VERSION 5.7 ;
  NOWIREEXTENSIONATPIN ON ;
  DIVIDERCHAR "/" ;
  BUSBITCHARS "[]" ;
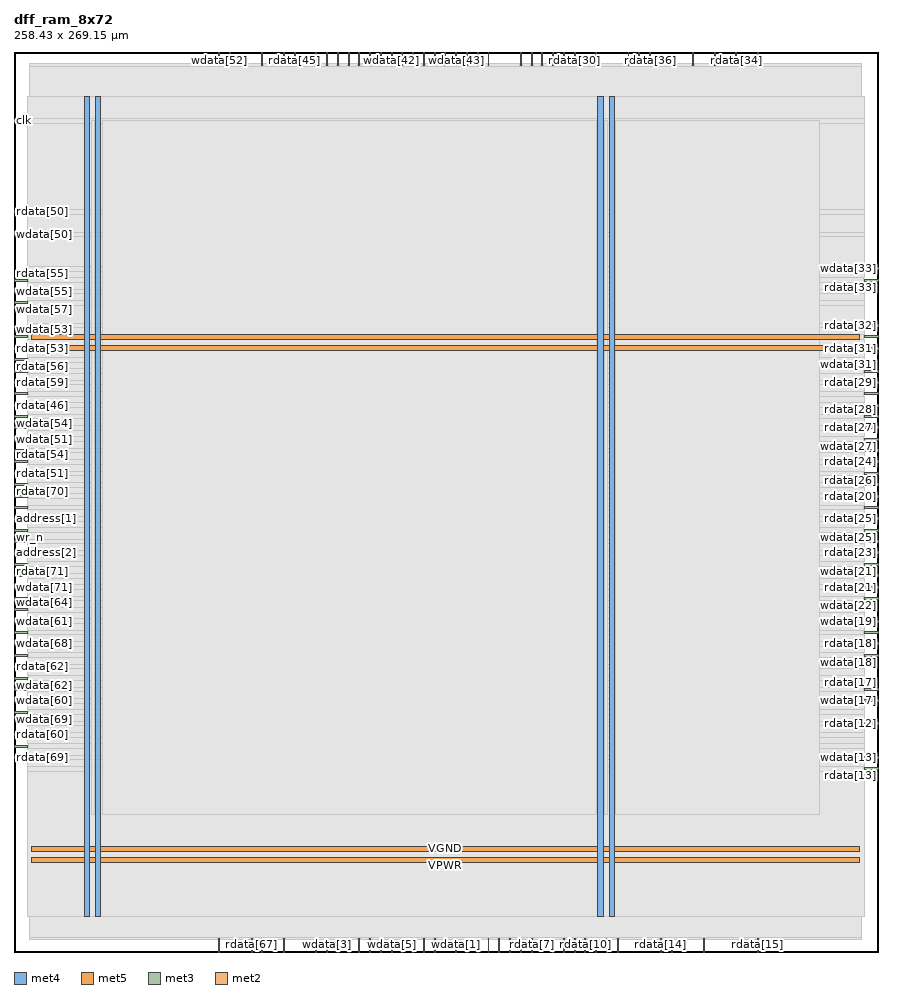
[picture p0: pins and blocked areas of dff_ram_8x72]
MACRO dff_ram_8x72
  CLASS BLOCK ;
  FOREIGN dff_ram_8x72 ;
  ORIGIN 0.000 0.000 ;
  SIZE 258.430 BY 269.150 ;
  PIN VGND
    DIRECTION INOUT ;
    USE GROUND ;
    PORT
      LAYER met4 ;
        RECT 24.340 10.640 25.940 255.920 ;
    END
    PORT
      LAYER met4 ;
        RECT 177.940 10.640 179.540 255.920 ;
    END
    PORT
      LAYER met5 ;
        RECT 5.280 30.030 252.780 31.630 ;
    END
    PORT
      LAYER met5 ;
        RECT 5.280 183.210 252.780 184.810 ;
    END
  END VGND
  PIN VPWR
    DIRECTION INOUT ;
    USE POWER ;
    PORT
      LAYER met4 ;
        RECT 21.040 10.640 22.640 255.920 ;
    END
    PORT
      LAYER met4 ;
        RECT 174.640 10.640 176.240 255.920 ;
    END
    PORT
      LAYER met5 ;
        RECT 5.280 26.730 252.780 28.330 ;
    END
    PORT
      LAYER met5 ;
        RECT 5.280 179.910 252.780 181.510 ;
    END
  END VPWR
  PIN address[0]
    DIRECTION INPUT ;
    USE SIGNAL ;
    ANTENNAGATEAREA 0.213000 ;
    PORT
      LAYER met3 ;
        RECT 0.000 132.640 4.000 133.240 ;
    END
  END address[0]
  PIN address[1]
    DIRECTION INPUT ;
    USE SIGNAL ;
    ANTENNAGATEAREA 0.213000 ;
    PORT
      LAYER met3 ;
        RECT 0.000 129.240 4.000 129.840 ;
    END
  END address[1]
  PIN address[2]
    DIRECTION INPUT ;
    USE SIGNAL ;
    ANTENNAGATEAREA 0.126000 ;
    PORT
      LAYER met3 ;
        RECT 0.000 119.040 4.000 119.640 ;
    END
  END address[2]
  PIN clk
    DIRECTION INPUT ;
    USE SIGNAL ;
    ANTENNAGATEAREA 0.852000 ;
    PORT
      LAYER met3 ;
        RECT 0.000 248.240 4.000 248.840 ;
    END
  END clk
  PIN rdata[0]
    DIRECTION OUTPUT TRISTATE ;
    USE SIGNAL ;
    ANTENNADIFFAREA 0.795200 ;
    PORT
      LAYER met2 ;
        RECT 119.230 0.000 119.510 4.000 ;
    END
  END rdata[0]
  PIN rdata[10]
    DIRECTION OUTPUT TRISTATE ;
    USE SIGNAL ;
    ANTENNADIFFAREA 0.795200 ;
    PORT
      LAYER met2 ;
        RECT 170.750 0.000 171.030 4.000 ;
    END
  END rdata[10]
  PIN rdata[11]
    DIRECTION OUTPUT TRISTATE ;
    USE SIGNAL ;
    ANTENNADIFFAREA 0.795200 ;
    PORT
      LAYER met2 ;
        RECT 173.970 0.000 174.250 4.000 ;
    END
  END rdata[11]
  PIN rdata[12]
    DIRECTION OUTPUT TRISTATE ;
    USE SIGNAL ;
    ANTENNADIFFAREA 0.795200 ;
    PORT
      LAYER met3 ;
        RECT 254.430 68.040 258.430 68.640 ;
    END
  END rdata[12]
  PIN rdata[13]
    DIRECTION OUTPUT TRISTATE ;
    USE SIGNAL ;
    ANTENNADIFFAREA 0.795200 ;
    PORT
      LAYER met3 ;
        RECT 254.430 54.440 258.430 55.040 ;
    END
  END rdata[13]
  PIN rdata[14]
    DIRECTION OUTPUT TRISTATE ;
    USE SIGNAL ;
    ANTENNADIFFAREA 0.795200 ;
    PORT
      LAYER met2 ;
        RECT 193.290 0.000 193.570 4.000 ;
    END
  END rdata[14]
  PIN rdata[15]
    DIRECTION OUTPUT TRISTATE ;
    USE SIGNAL ;
    ANTENNADIFFAREA 0.795200 ;
    PORT
      LAYER met2 ;
        RECT 222.270 0.000 222.550 4.000 ;
    END
  END rdata[15]
  PIN rdata[16]
    DIRECTION OUTPUT TRISTATE ;
    USE SIGNAL ;
    ANTENNADIFFAREA 0.795200 ;
    PORT
      LAYER met2 ;
        RECT 196.510 0.000 196.790 4.000 ;
    END
  END rdata[16]
  PIN rdata[17]
    DIRECTION OUTPUT TRISTATE ;
    USE SIGNAL ;
    ANTENNADIFFAREA 0.445500 ;
    PORT
      LAYER met3 ;
        RECT 254.430 78.240 258.430 78.840 ;
    END
  END rdata[17]
  PIN rdata[18]
    DIRECTION OUTPUT TRISTATE ;
    USE SIGNAL ;
    ANTENNADIFFAREA 0.795200 ;
    PORT
      LAYER met3 ;
        RECT 254.430 91.840 258.430 92.440 ;
    END
  END rdata[18]
  PIN rdata[19]
    DIRECTION OUTPUT TRISTATE ;
    USE SIGNAL ;
    ANTENNADIFFAREA 0.795200 ;
    PORT
      LAYER met3 ;
        RECT 254.430 95.240 258.430 95.840 ;
    END
  END rdata[19]
  PIN rdata[1]
    DIRECTION OUTPUT TRISTATE ;
    USE SIGNAL ;
    ANTENNADIFFAREA 0.795200 ;
    PORT
      LAYER met2 ;
        RECT 144.990 0.000 145.270 4.000 ;
    END
  END rdata[1]
  PIN rdata[20]
    DIRECTION OUTPUT TRISTATE ;
    USE SIGNAL ;
    ANTENNADIFFAREA 0.795200 ;
    PORT
      LAYER met3 ;
        RECT 254.430 136.040 258.430 136.640 ;
    END
  END rdata[20]
  PIN rdata[21]
    DIRECTION OUTPUT TRISTATE ;
    USE SIGNAL ;
    ANTENNADIFFAREA 0.795200 ;
    PORT
      LAYER met3 ;
        RECT 254.430 108.840 258.430 109.440 ;
    END
  END rdata[21]
  PIN rdata[22]
    DIRECTION OUTPUT TRISTATE ;
    USE SIGNAL ;
    ANTENNADIFFAREA 0.795200 ;
    PORT
      LAYER met3 ;
        RECT 254.430 112.240 258.430 112.840 ;
    END
  END rdata[22]
  PIN rdata[23]
    DIRECTION OUTPUT TRISTATE ;
    USE SIGNAL ;
    ANTENNADIFFAREA 0.795200 ;
    PORT
      LAYER met3 ;
        RECT 254.430 119.040 258.430 119.640 ;
    END
  END rdata[23]
  PIN rdata[24]
    DIRECTION OUTPUT TRISTATE ;
    USE SIGNAL ;
    ANTENNADIFFAREA 0.795200 ;
    PORT
      LAYER met3 ;
        RECT 254.430 146.240 258.430 146.840 ;
    END
  END rdata[24]
  PIN rdata[25]
    DIRECTION OUTPUT TRISTATE ;
    USE SIGNAL ;
    ANTENNADIFFAREA 0.795200 ;
    PORT
      LAYER met3 ;
        RECT 254.430 129.240 258.430 129.840 ;
    END
  END rdata[25]
  PIN rdata[26]
    DIRECTION OUTPUT TRISTATE ;
    USE SIGNAL ;
    ANTENNADIFFAREA 0.795200 ;
    PORT
      LAYER met3 ;
        RECT 254.430 142.840 258.430 143.440 ;
    END
  END rdata[26]
  PIN rdata[27]
    DIRECTION OUTPUT TRISTATE ;
    USE SIGNAL ;
    ANTENNADIFFAREA 0.795200 ;
    PORT
      LAYER met3 ;
        RECT 254.430 156.440 258.430 157.040 ;
    END
  END rdata[27]
  PIN rdata[28]
    DIRECTION OUTPUT TRISTATE ;
    USE SIGNAL ;
    ANTENNADIFFAREA 0.795200 ;
    PORT
      LAYER met3 ;
        RECT 254.430 159.840 258.430 160.440 ;
    END
  END rdata[28]
  PIN rdata[29]
    DIRECTION OUTPUT TRISTATE ;
    USE SIGNAL ;
    ANTENNADIFFAREA 0.795200 ;
    PORT
      LAYER met3 ;
        RECT 254.430 170.040 258.430 170.640 ;
    END
  END rdata[29]
  PIN rdata[2]
    DIRECTION OUTPUT TRISTATE ;
    USE SIGNAL ;
    ANTENNADIFFAREA 0.795200 ;
    PORT
      LAYER met2 ;
        RECT 125.670 0.000 125.950 4.000 ;
    END
  END rdata[2]
  PIN rdata[30]
    DIRECTION OUTPUT TRISTATE ;
    USE SIGNAL ;
    ANTENNADIFFAREA 0.795200 ;
    PORT
      LAYER met2 ;
        RECT 167.530 265.150 167.810 269.150 ;
    END
  END rdata[30]
  PIN rdata[31]
    DIRECTION OUTPUT TRISTATE ;
    USE SIGNAL ;
    ANTENNADIFFAREA 0.445500 ;
    PORT
      LAYER met3 ;
        RECT 254.430 180.240 258.430 180.840 ;
    END
  END rdata[31]
  PIN rdata[32]
    DIRECTION OUTPUT TRISTATE ;
    USE SIGNAL ;
    ANTENNADIFFAREA 0.445500 ;
    PORT
      LAYER met3 ;
        RECT 254.430 187.040 258.430 187.640 ;
    END
  END rdata[32]
  PIN rdata[33]
    DIRECTION OUTPUT TRISTATE ;
    USE SIGNAL ;
    ANTENNADIFFAREA 0.445500 ;
    PORT
      LAYER met3 ;
        RECT 254.430 200.640 258.430 201.240 ;
    END
  END rdata[33]
  PIN rdata[34]
    DIRECTION OUTPUT TRISTATE ;
    USE SIGNAL ;
    ANTENNADIFFAREA 0.795200 ;
    PORT
      LAYER met2 ;
        RECT 215.830 265.150 216.110 269.150 ;
    END
  END rdata[34]
  PIN rdata[35]
    DIRECTION OUTPUT TRISTATE ;
    USE SIGNAL ;
    ANTENNADIFFAREA 0.795200 ;
    PORT
      LAYER met2 ;
        RECT 183.630 265.150 183.910 269.150 ;
    END
  END rdata[35]
  PIN rdata[36]
    DIRECTION OUTPUT TRISTATE ;
    USE SIGNAL ;
    ANTENNADIFFAREA 0.795200 ;
    PORT
      LAYER met2 ;
        RECT 190.070 265.150 190.350 269.150 ;
    END
  END rdata[36]
  PIN rdata[37]
    DIRECTION OUTPUT TRISTATE ;
    USE SIGNAL ;
    ANTENNADIFFAREA 0.795200 ;
    PORT
      LAYER met2 ;
        RECT 164.310 265.150 164.590 269.150 ;
    END
  END rdata[37]
  PIN rdata[38]
    DIRECTION OUTPUT TRISTATE ;
    USE SIGNAL ;
    ANTENNADIFFAREA 0.795200 ;
    PORT
      LAYER met2 ;
        RECT 209.390 265.150 209.670 269.150 ;
    END
  END rdata[38]
  PIN rdata[39]
    DIRECTION OUTPUT TRISTATE ;
    USE SIGNAL ;
    ANTENNADIFFAREA 0.795200 ;
    PORT
      LAYER met2 ;
        RECT 161.090 265.150 161.370 269.150 ;
    END
  END rdata[39]
  PIN rdata[3]
    DIRECTION OUTPUT TRISTATE ;
    USE SIGNAL ;
    ANTENNADIFFAREA 0.795200 ;
    PORT
      LAYER met2 ;
        RECT 103.130 0.000 103.410 4.000 ;
    END
  END rdata[3]
  PIN rdata[40]
    DIRECTION OUTPUT TRISTATE ;
    USE SIGNAL ;
    ANTENNADIFFAREA 0.795200 ;
    PORT
      LAYER met2 ;
        RECT 138.550 265.150 138.830 269.150 ;
    END
  END rdata[40]
  PIN rdata[41]
    DIRECTION OUTPUT TRISTATE ;
    USE SIGNAL ;
    ANTENNADIFFAREA 0.795200 ;
    PORT
      LAYER met2 ;
        RECT 106.350 265.150 106.630 269.150 ;
    END
  END rdata[41]
  PIN rdata[42]
    DIRECTION OUTPUT TRISTATE ;
    USE SIGNAL ;
    ANTENNADIFFAREA 0.795200 ;
    PORT
      LAYER met2 ;
        RECT 119.230 265.150 119.510 269.150 ;
    END
  END rdata[42]
  PIN rdata[43]
    DIRECTION OUTPUT TRISTATE ;
    USE SIGNAL ;
    ANTENNADIFFAREA 0.795200 ;
    PORT
      LAYER met2 ;
        RECT 141.770 265.150 142.050 269.150 ;
    END
  END rdata[43]
  PIN rdata[44]
    DIRECTION OUTPUT TRISTATE ;
    USE SIGNAL ;
    ANTENNADIFFAREA 0.795200 ;
    PORT
      LAYER met2 ;
        RECT 122.450 265.150 122.730 269.150 ;
    END
  END rdata[44]
  PIN rdata[45]
    DIRECTION OUTPUT TRISTATE ;
    USE SIGNAL ;
    ANTENNADIFFAREA 0.795200 ;
    PORT
      LAYER met2 ;
        RECT 83.810 265.150 84.090 269.150 ;
    END
  END rdata[45]
  PIN rdata[46]
    DIRECTION OUTPUT TRISTATE ;
    USE SIGNAL ;
    ANTENNADIFFAREA 0.795200 ;
    PORT
      LAYER met3 ;
        RECT 0.000 163.240 4.000 163.840 ;
    END
  END rdata[46]
  PIN rdata[47]
    DIRECTION OUTPUT TRISTATE ;
    USE SIGNAL ;
    ANTENNADIFFAREA 0.795200 ;
    PORT
      LAYER met2 ;
        RECT 109.570 265.150 109.850 269.150 ;
    END
  END rdata[47]
  PIN rdata[48]
    DIRECTION OUTPUT TRISTATE ;
    USE SIGNAL ;
    ANTENNADIFFAREA 0.795200 ;
    PORT
      LAYER met2 ;
        RECT 135.330 265.150 135.610 269.150 ;
    END
  END rdata[48]
  PIN rdata[49]
    DIRECTION OUTPUT TRISTATE ;
    USE SIGNAL ;
    ANTENNADIFFAREA 0.795200 ;
    PORT
      LAYER met2 ;
        RECT 96.690 265.150 96.970 269.150 ;
    END
  END rdata[49]
  PIN rdata[4]
    DIRECTION OUTPUT TRISTATE ;
    USE SIGNAL ;
    ANTENNADIFFAREA 0.795200 ;
    PORT
      LAYER met2 ;
        RECT 106.350 0.000 106.630 4.000 ;
    END
  END rdata[4]
  PIN rdata[50]
    DIRECTION OUTPUT TRISTATE ;
    USE SIGNAL ;
    ANTENNADIFFAREA 0.795200 ;
    PORT
      LAYER met3 ;
        RECT 0.000 221.040 4.000 221.640 ;
    END
  END rdata[50]
  PIN rdata[51]
    DIRECTION OUTPUT TRISTATE ;
    USE SIGNAL ;
    ANTENNADIFFAREA 0.795200 ;
    PORT
      LAYER met3 ;
        RECT 0.000 142.840 4.000 143.440 ;
    END
  END rdata[51]
  PIN rdata[52]
    DIRECTION OUTPUT TRISTATE ;
    USE SIGNAL ;
    ANTENNADIFFAREA 0.795200 ;
    PORT
      LAYER met2 ;
        RECT 64.490 265.150 64.770 269.150 ;
    END
  END rdata[52]
  PIN rdata[53]
    DIRECTION OUTPUT TRISTATE ;
    USE SIGNAL ;
    ANTENNADIFFAREA 0.795200 ;
    PORT
      LAYER met3 ;
        RECT 0.000 180.240 4.000 180.840 ;
    END
  END rdata[53]
  PIN rdata[54]
    DIRECTION OUTPUT TRISTATE ;
    USE SIGNAL ;
    ANTENNADIFFAREA 0.795200 ;
    PORT
      LAYER met3 ;
        RECT 0.000 146.240 4.000 146.840 ;
    END
  END rdata[54]
  PIN rdata[55]
    DIRECTION OUTPUT TRISTATE ;
    USE SIGNAL ;
    ANTENNADIFFAREA 0.795200 ;
    PORT
      LAYER met3 ;
        RECT 0.000 200.640 4.000 201.240 ;
    END
  END rdata[55]
  PIN rdata[56]
    DIRECTION OUTPUT TRISTATE ;
    USE SIGNAL ;
    ANTENNADIFFAREA 0.795200 ;
    PORT
      LAYER met3 ;
        RECT 0.000 176.840 4.000 177.440 ;
    END
  END rdata[56]
  PIN rdata[57]
    DIRECTION OUTPUT TRISTATE ;
    USE SIGNAL ;
    ANTENNADIFFAREA 0.795200 ;
    PORT
      LAYER met2 ;
        RECT 74.150 265.150 74.430 269.150 ;
    END
  END rdata[57]
  PIN rdata[58]
    DIRECTION OUTPUT TRISTATE ;
    USE SIGNAL ;
    ANTENNADIFFAREA 0.795200 ;
    PORT
      LAYER met3 ;
        RECT 0.000 149.640 4.000 150.240 ;
    END
  END rdata[58]
  PIN rdata[59]
    DIRECTION OUTPUT TRISTATE ;
    USE SIGNAL ;
    ANTENNADIFFAREA 0.795200 ;
    PORT
      LAYER met3 ;
        RECT 0.000 170.040 4.000 170.640 ;
    END
  END rdata[59]
  PIN rdata[5]
    DIRECTION OUTPUT TRISTATE ;
    USE SIGNAL ;
    ANTENNADIFFAREA 0.795200 ;
    PORT
      LAYER met2 ;
        RECT 122.450 0.000 122.730 4.000 ;
    END
  END rdata[5]
  PIN rdata[60]
    DIRECTION OUTPUT TRISTATE ;
    USE SIGNAL ;
    ANTENNADIFFAREA 0.795200 ;
    PORT
      LAYER met3 ;
        RECT 0.000 64.640 4.000 65.240 ;
    END
  END rdata[60]
  PIN rdata[61]
    DIRECTION OUTPUT TRISTATE ;
    USE SIGNAL ;
    ANTENNADIFFAREA 0.795200 ;
    PORT
      LAYER met3 ;
        RECT 0.000 122.440 4.000 123.040 ;
    END
  END rdata[61]
  PIN rdata[62]
    DIRECTION OUTPUT TRISTATE ;
    USE SIGNAL ;
    ANTENNADIFFAREA 0.795200 ;
    PORT
      LAYER met3 ;
        RECT 0.000 85.040 4.000 85.640 ;
    END
  END rdata[62]
  PIN rdata[63]
    DIRECTION OUTPUT TRISTATE ;
    USE SIGNAL ;
    ANTENNADIFFAREA 0.795200 ;
    PORT
      LAYER met2 ;
        RECT 80.590 0.000 80.870 4.000 ;
    END
  END rdata[63]
  PIN rdata[64]
    DIRECTION OUTPUT TRISTATE ;
    USE SIGNAL ;
    ANTENNADIFFAREA 0.795200 ;
    PORT
      LAYER met3 ;
        RECT 0.000 95.240 4.000 95.840 ;
    END
  END rdata[64]
  PIN rdata[65]
    DIRECTION OUTPUT TRISTATE ;
    USE SIGNAL ;
    ANTENNADIFFAREA 0.795200 ;
    PORT
      LAYER met3 ;
        RECT 0.000 61.240 4.000 61.840 ;
    END
  END rdata[65]
  PIN rdata[66]
    DIRECTION OUTPUT TRISTATE ;
    USE SIGNAL ;
    ANTENNADIFFAREA 0.795200 ;
    PORT
      LAYER met3 ;
        RECT 0.000 112.240 4.000 112.840 ;
    END
  END rdata[66]
  PIN rdata[67]
    DIRECTION OUTPUT TRISTATE ;
    USE SIGNAL ;
    ANTENNADIFFAREA 0.795200 ;
    PORT
      LAYER met2 ;
        RECT 70.930 0.000 71.210 4.000 ;
    END
  END rdata[67]
  PIN rdata[68]
    DIRECTION OUTPUT TRISTATE ;
    USE SIGNAL ;
    ANTENNADIFFAREA 0.795200 ;
    PORT
      LAYER met3 ;
        RECT 0.000 105.440 4.000 106.040 ;
    END
  END rdata[68]
  PIN rdata[69]
    DIRECTION OUTPUT TRISTATE ;
    USE SIGNAL ;
    ANTENNADIFFAREA 0.795200 ;
    PORT
      LAYER met3 ;
        RECT 0.000 57.840 4.000 58.440 ;
    END
  END rdata[69]
  PIN rdata[6]
    DIRECTION OUTPUT TRISTATE ;
    USE SIGNAL ;
    ANTENNADIFFAREA 0.795200 ;
    PORT
      LAYER met2 ;
        RECT 99.910 0.000 100.190 4.000 ;
    END
  END rdata[6]
  PIN rdata[70]
    DIRECTION OUTPUT TRISTATE ;
    USE SIGNAL ;
    ANTENNADIFFAREA 0.795200 ;
    PORT
      LAYER met3 ;
        RECT 0.000 139.440 4.000 140.040 ;
    END
  END rdata[70]
  PIN rdata[71]
    DIRECTION OUTPUT TRISTATE ;
    USE SIGNAL ;
    ANTENNADIFFAREA 0.795200 ;
    PORT
      LAYER met3 ;
        RECT 0.000 115.640 4.000 116.240 ;
    END
  END rdata[71]
  PIN rdata[7]
    DIRECTION OUTPUT TRISTATE ;
    USE SIGNAL ;
    ANTENNADIFFAREA 0.795200 ;
    PORT
      LAYER met2 ;
        RECT 154.650 0.000 154.930 4.000 ;
    END
  END rdata[7]
  PIN rdata[8]
    DIRECTION OUTPUT TRISTATE ;
    USE SIGNAL ;
    ANTENNADIFFAREA 0.795200 ;
    PORT
      LAYER met2 ;
        RECT 151.430 0.000 151.710 4.000 ;
    END
  END rdata[8]
  PIN rdata[9]
    DIRECTION OUTPUT TRISTATE ;
    USE SIGNAL ;
    ANTENNADIFFAREA 0.795200 ;
    PORT
      LAYER met2 ;
        RECT 148.210 0.000 148.490 4.000 ;
    END
  END rdata[9]
  PIN wdata[0]
    DIRECTION INPUT ;
    USE SIGNAL ;
    ANTENNAGATEAREA 0.213000 ;
    PORT
      LAYER met2 ;
        RECT 109.570 0.000 109.850 4.000 ;
    END
  END wdata[0]
  PIN wdata[10]
    DIRECTION INPUT ;
    USE SIGNAL ;
    ANTENNAGATEAREA 0.213000 ;
    PORT
      LAYER met2 ;
        RECT 164.310 0.000 164.590 4.000 ;
    END
  END wdata[10]
  PIN wdata[11]
    DIRECTION INPUT ;
    USE SIGNAL ;
    ANTENNAGATEAREA 0.159000 ;
    PORT
      LAYER met2 ;
        RECT 161.090 0.000 161.370 4.000 ;
    END
  END wdata[11]
  PIN wdata[12]
    DIRECTION INPUT ;
    USE SIGNAL ;
    ANTENNAGATEAREA 0.159000 ;
    PORT
      LAYER met2 ;
        RECT 177.190 0.000 177.470 4.000 ;
    END
  END wdata[12]
  PIN wdata[13]
    DIRECTION INPUT ;
    USE SIGNAL ;
    ANTENNAGATEAREA 0.213000 ;
    PORT
      LAYER met3 ;
        RECT 254.430 57.840 258.430 58.440 ;
    END
  END wdata[13]
  PIN wdata[14]
    DIRECTION INPUT ;
    USE SIGNAL ;
    ANTENNAGATEAREA 0.213000 ;
    PORT
      LAYER met2 ;
        RECT 167.530 0.000 167.810 4.000 ;
    END
  END wdata[14]
  PIN wdata[15]
    DIRECTION INPUT ;
    USE SIGNAL ;
    ANTENNAGATEAREA 0.213000 ;
    PORT
      LAYER met2 ;
        RECT 206.170 0.000 206.450 4.000 ;
    END
  END wdata[15]
  PIN wdata[16]
    DIRECTION INPUT ;
    USE SIGNAL ;
    ANTENNAGATEAREA 0.213000 ;
    PORT
      LAYER met2 ;
        RECT 180.410 0.000 180.690 4.000 ;
    END
  END wdata[16]
  PIN wdata[17]
    DIRECTION INPUT ;
    USE SIGNAL ;
    ANTENNAGATEAREA 0.213000 ;
    PORT
      LAYER met3 ;
        RECT 254.430 74.840 258.430 75.440 ;
    END
  END wdata[17]
  PIN wdata[18]
    DIRECTION INPUT ;
    USE SIGNAL ;
    ANTENNAGATEAREA 0.213000 ;
    PORT
      LAYER met3 ;
        RECT 254.430 88.440 258.430 89.040 ;
    END
  END wdata[18]
  PIN wdata[19]
    DIRECTION INPUT ;
    USE SIGNAL ;
    ANTENNAGATEAREA 0.213000 ;
    PORT
      LAYER met3 ;
        RECT 254.430 98.640 258.430 99.240 ;
    END
  END wdata[19]
  PIN wdata[1]
    DIRECTION INPUT ;
    USE SIGNAL ;
    ANTENNAGATEAREA 0.213000 ;
    PORT
      LAYER met2 ;
        RECT 132.110 0.000 132.390 4.000 ;
    END
  END wdata[1]
  PIN wdata[20]
    DIRECTION INPUT ;
    USE SIGNAL ;
    ANTENNAGATEAREA 0.159000 ;
    PORT
      LAYER met3 ;
        RECT 254.430 132.640 258.430 133.240 ;
    END
  END wdata[20]
  PIN wdata[21]
    DIRECTION INPUT ;
    USE SIGNAL ;
    ANTENNAGATEAREA 0.213000 ;
    PORT
      LAYER met3 ;
        RECT 254.430 115.640 258.430 116.240 ;
    END
  END wdata[21]
  PIN wdata[22]
    DIRECTION INPUT ;
    USE SIGNAL ;
    ANTENNAGATEAREA 0.159000 ;
    PORT
      LAYER met3 ;
        RECT 254.430 105.440 258.430 106.040 ;
    END
  END wdata[22]
  PIN wdata[23]
    DIRECTION INPUT ;
    USE SIGNAL ;
    ANTENNAGATEAREA 0.159000 ;
    PORT
      LAYER met3 ;
        RECT 254.430 122.440 258.430 123.040 ;
    END
  END wdata[23]
  PIN wdata[24]
    DIRECTION INPUT ;
    USE SIGNAL ;
    ANTENNAGATEAREA 0.213000 ;
    PORT
      LAYER met3 ;
        RECT 254.430 149.640 258.430 150.240 ;
    END
  END wdata[24]
  PIN wdata[25]
    DIRECTION INPUT ;
    USE SIGNAL ;
    ANTENNAGATEAREA 0.213000 ;
    PORT
      LAYER met3 ;
        RECT 254.430 125.840 258.430 126.440 ;
    END
  END wdata[25]
  PIN wdata[26]
    DIRECTION INPUT ;
    USE SIGNAL ;
    ANTENNAGATEAREA 0.213000 ;
    PORT
      LAYER met3 ;
        RECT 254.430 139.440 258.430 140.040 ;
    END
  END wdata[26]
  PIN wdata[27]
    DIRECTION INPUT ;
    USE SIGNAL ;
    ANTENNAGATEAREA 0.213000 ;
    PORT
      LAYER met3 ;
        RECT 254.430 153.040 258.430 153.640 ;
    END
  END wdata[27]
  PIN wdata[28]
    DIRECTION INPUT ;
    USE SIGNAL ;
    ANTENNAGATEAREA 0.159000 ;
    PORT
      LAYER met3 ;
        RECT 254.430 163.240 258.430 163.840 ;
    END
  END wdata[28]
  PIN wdata[29]
    DIRECTION INPUT ;
    USE SIGNAL ;
    ANTENNAGATEAREA 0.213000 ;
    PORT
      LAYER met3 ;
        RECT 254.430 166.640 258.430 167.240 ;
    END
  END wdata[29]
  PIN wdata[2]
    DIRECTION INPUT ;
    USE SIGNAL ;
    ANTENNAGATEAREA 0.159000 ;
    PORT
      LAYER met2 ;
        RECT 116.010 0.000 116.290 4.000 ;
    END
  END wdata[2]
  PIN wdata[30]
    DIRECTION INPUT ;
    USE SIGNAL ;
    ANTENNAGATEAREA 0.213000 ;
    PORT
      LAYER met2 ;
        RECT 157.870 265.150 158.150 269.150 ;
    END
  END wdata[30]
  PIN wdata[31]
    DIRECTION INPUT ;
    USE SIGNAL ;
    ANTENNAGATEAREA 0.159000 ;
    PORT
      LAYER met3 ;
        RECT 254.430 173.440 258.430 174.040 ;
    END
  END wdata[31]
  PIN wdata[32]
    DIRECTION INPUT ;
    USE SIGNAL ;
    ANTENNAGATEAREA 0.213000 ;
    PORT
      LAYER met3 ;
        RECT 254.430 183.640 258.430 184.240 ;
    END
  END wdata[32]
  PIN wdata[33]
    DIRECTION INPUT ;
    USE SIGNAL ;
    ANTENNAGATEAREA 0.213000 ;
    PORT
      LAYER met3 ;
        RECT 254.430 204.040 258.430 204.640 ;
    END
  END wdata[33]
  PIN wdata[34]
    DIRECTION INPUT ;
    USE SIGNAL ;
    ANTENNAGATEAREA 0.213000 ;
    PORT
      LAYER met2 ;
        RECT 222.270 265.150 222.550 269.150 ;
    END
  END wdata[34]
  PIN wdata[35]
    DIRECTION INPUT ;
    USE SIGNAL ;
    ANTENNAGATEAREA 0.213000 ;
    PORT
      LAYER met2 ;
        RECT 173.970 265.150 174.250 269.150 ;
    END
  END wdata[35]
  PIN wdata[36]
    DIRECTION INPUT ;
    USE SIGNAL ;
    ANTENNAGATEAREA 0.213000 ;
    PORT
      LAYER met2 ;
        RECT 186.850 265.150 187.130 269.150 ;
    END
  END wdata[36]
  PIN wdata[37]
    DIRECTION INPUT ;
    USE SIGNAL ;
    ANTENNAGATEAREA 0.159000 ;
    PORT
      LAYER met2 ;
        RECT 154.650 265.150 154.930 269.150 ;
    END
  END wdata[37]
  PIN wdata[38]
    DIRECTION INPUT ;
    USE SIGNAL ;
    ANTENNAGATEAREA 0.213000 ;
    PORT
      LAYER met2 ;
        RECT 202.950 265.150 203.230 269.150 ;
    END
  END wdata[38]
  PIN wdata[39]
    DIRECTION INPUT ;
    USE SIGNAL ;
    ANTENNAGATEAREA 0.213000 ;
    PORT
      LAYER met2 ;
        RECT 151.430 265.150 151.710 269.150 ;
    END
  END wdata[39]
  PIN wdata[3]
    DIRECTION INPUT ;
    USE SIGNAL ;
    ANTENNAGATEAREA 0.213000 ;
    PORT
      LAYER met2 ;
        RECT 93.470 0.000 93.750 4.000 ;
    END
  END wdata[3]
  PIN wdata[40]
    DIRECTION INPUT ;
    USE SIGNAL ;
    ANTENNAGATEAREA 0.159000 ;
    PORT
      LAYER met2 ;
        RECT 128.890 265.150 129.170 269.150 ;
    END
  END wdata[40]
  PIN wdata[41]
    DIRECTION INPUT ;
    USE SIGNAL ;
    ANTENNAGATEAREA 0.213000 ;
    PORT
      LAYER met2 ;
        RECT 99.910 265.150 100.190 269.150 ;
    END
  END wdata[41]
  PIN wdata[42]
    DIRECTION INPUT ;
    USE SIGNAL ;
    ANTENNAGATEAREA 0.213000 ;
    PORT
      LAYER met2 ;
        RECT 112.790 265.150 113.070 269.150 ;
    END
  END wdata[42]
  PIN wdata[43]
    DIRECTION INPUT ;
    USE SIGNAL ;
    ANTENNAGATEAREA 0.213000 ;
    PORT
      LAYER met2 ;
        RECT 132.110 265.150 132.390 269.150 ;
    END
  END wdata[43]
  PIN wdata[44]
    DIRECTION INPUT ;
    USE SIGNAL ;
    ANTENNAGATEAREA 0.213000 ;
    PORT
      LAYER met2 ;
        RECT 116.010 265.150 116.290 269.150 ;
    END
  END wdata[44]
  PIN wdata[45]
    DIRECTION INPUT ;
    USE SIGNAL ;
    ANTENNAGATEAREA 0.213000 ;
    PORT
      LAYER met2 ;
        RECT 80.590 265.150 80.870 269.150 ;
    END
  END wdata[45]
  PIN wdata[46]
    DIRECTION INPUT ;
    USE SIGNAL ;
    ANTENNAGATEAREA 0.159000 ;
    PORT
      LAYER met2 ;
        RECT 103.130 265.150 103.410 269.150 ;
    END
  END wdata[46]
  PIN wdata[47]
    DIRECTION INPUT ;
    USE SIGNAL ;
    ANTENNAGATEAREA 0.159000 ;
    PORT
      LAYER met2 ;
        RECT 93.470 265.150 93.750 269.150 ;
    END
  END wdata[47]
  PIN wdata[48]
    DIRECTION INPUT ;
    USE SIGNAL ;
    ANTENNAGATEAREA 0.213000 ;
    PORT
      LAYER met2 ;
        RECT 125.670 265.150 125.950 269.150 ;
    END
  END wdata[48]
  PIN wdata[49]
    DIRECTION INPUT ;
    USE SIGNAL ;
    ANTENNAGATEAREA 0.213000 ;
    PORT
      LAYER met2 ;
        RECT 90.250 265.150 90.530 269.150 ;
    END
  END wdata[49]
  PIN wdata[4]
    DIRECTION INPUT ;
    USE SIGNAL ;
    ANTENNAGATEAREA 0.159000 ;
    PORT
      LAYER met2 ;
        RECT 96.690 0.000 96.970 4.000 ;
    END
  END wdata[4]
  PIN wdata[50]
    DIRECTION INPUT ;
    USE SIGNAL ;
    ANTENNAGATEAREA 0.213000 ;
    PORT
      LAYER met3 ;
        RECT 0.000 214.240 4.000 214.840 ;
    END
  END wdata[50]
  PIN wdata[51]
    DIRECTION INPUT ;
    USE SIGNAL ;
    ANTENNAGATEAREA 0.213000 ;
    PORT
      LAYER met3 ;
        RECT 0.000 153.040 4.000 153.640 ;
    END
  END wdata[51]
  PIN wdata[52]
    DIRECTION INPUT ;
    USE SIGNAL ;
    ANTENNAGATEAREA 0.213000 ;
    PORT
      LAYER met2 ;
        RECT 61.270 265.150 61.550 269.150 ;
    END
  END wdata[52]
  PIN wdata[53]
    DIRECTION INPUT ;
    USE SIGNAL ;
    ANTENNAGATEAREA 0.213000 ;
    PORT
      LAYER met3 ;
        RECT 0.000 183.640 4.000 184.240 ;
    END
  END wdata[53]
  PIN wdata[54]
    DIRECTION INPUT ;
    USE SIGNAL ;
    ANTENNAGATEAREA 0.213000 ;
    PORT
      LAYER met3 ;
        RECT 0.000 159.840 4.000 160.440 ;
    END
  END wdata[54]
  PIN wdata[55]
    DIRECTION INPUT ;
    USE SIGNAL ;
    ANTENNAGATEAREA 0.213000 ;
    PORT
      LAYER met3 ;
        RECT 0.000 197.240 4.000 197.840 ;
    END
  END wdata[55]
  PIN wdata[56]
    DIRECTION INPUT ;
    USE SIGNAL ;
    ANTENNAGATEAREA 0.213000 ;
    PORT
      LAYER met3 ;
        RECT 0.000 173.440 4.000 174.040 ;
    END
  END wdata[56]
  PIN wdata[57]
    DIRECTION INPUT ;
    USE SIGNAL ;
    ANTENNAGATEAREA 0.159000 ;
    PORT
      LAYER met3 ;
        RECT 0.000 193.840 4.000 194.440 ;
    END
  END wdata[57]
  PIN wdata[58]
    DIRECTION INPUT ;
    USE SIGNAL ;
    ANTENNAGATEAREA 0.213000 ;
    PORT
      LAYER met3 ;
        RECT 0.000 156.440 4.000 157.040 ;
    END
  END wdata[58]
  PIN wdata[59]
    DIRECTION INPUT ;
    USE SIGNAL ;
    ANTENNAGATEAREA 0.213000 ;
    PORT
      LAYER met3 ;
        RECT 0.000 166.640 4.000 167.240 ;
    END
  END wdata[59]
  PIN wdata[5]
    DIRECTION INPUT ;
    USE SIGNAL ;
    ANTENNAGATEAREA 0.213000 ;
    PORT
      LAYER met2 ;
        RECT 112.790 0.000 113.070 4.000 ;
    END
  END wdata[5]
  PIN wdata[60]
    DIRECTION INPUT ;
    USE SIGNAL ;
    ANTENNAGATEAREA 0.213000 ;
    PORT
      LAYER met3 ;
        RECT 0.000 74.840 4.000 75.440 ;
    END
  END wdata[60]
  PIN wdata[61]
    DIRECTION INPUT ;
    USE SIGNAL ;
    ANTENNAGATEAREA 0.213000 ;
    PORT
      LAYER met3 ;
        RECT 0.000 98.640 4.000 99.240 ;
    END
  END wdata[61]
  PIN wdata[62]
    DIRECTION INPUT ;
    USE SIGNAL ;
    ANTENNAGATEAREA 0.213000 ;
    PORT
      LAYER met3 ;
        RECT 0.000 81.640 4.000 82.240 ;
    END
  END wdata[62]
  PIN wdata[63]
    DIRECTION INPUT ;
    USE SIGNAL ;
    ANTENNAGATEAREA 0.213000 ;
    PORT
      LAYER met2 ;
        RECT 74.150 0.000 74.430 4.000 ;
    END
  END wdata[63]
  PIN wdata[64]
    DIRECTION INPUT ;
    USE SIGNAL ;
    ANTENNAGATEAREA 0.213000 ;
    PORT
      LAYER met3 ;
        RECT 0.000 102.040 4.000 102.640 ;
    END
  END wdata[64]
  PIN wdata[65]
    DIRECTION INPUT ;
    USE SIGNAL ;
    ANTENNAGATEAREA 0.213000 ;
    PORT
      LAYER met3 ;
        RECT 0.000 78.240 4.000 78.840 ;
    END
  END wdata[65]
  PIN wdata[66]
    DIRECTION INPUT ;
    USE SIGNAL ;
    ANTENNAGATEAREA 0.213000 ;
    PORT
      LAYER met3 ;
        RECT 0.000 88.440 4.000 89.040 ;
    END
  END wdata[66]
  PIN wdata[67]
    DIRECTION INPUT ;
    USE SIGNAL ;
    ANTENNAGATEAREA 0.213000 ;
    PORT
      LAYER met2 ;
        RECT 61.270 0.000 61.550 4.000 ;
    END
  END wdata[67]
  PIN wdata[68]
    DIRECTION INPUT ;
    USE SIGNAL ;
    ANTENNAGATEAREA 0.159000 ;
    PORT
      LAYER met3 ;
        RECT 0.000 91.840 4.000 92.440 ;
    END
  END wdata[68]
  PIN wdata[69]
    DIRECTION INPUT ;
    USE SIGNAL ;
    ANTENNAGATEAREA 0.213000 ;
    PORT
      LAYER met3 ;
        RECT 0.000 71.440 4.000 72.040 ;
    END
  END wdata[69]
  PIN wdata[6]
    DIRECTION INPUT ;
    USE SIGNAL ;
    ANTENNAGATEAREA 0.213000 ;
    PORT
      LAYER met2 ;
        RECT 90.250 0.000 90.530 4.000 ;
    END
  END wdata[6]
  PIN wdata[70]
    DIRECTION INPUT ;
    USE SIGNAL ;
    ANTENNAGATEAREA 0.159000 ;
    PORT
      LAYER met3 ;
        RECT 0.000 136.040 4.000 136.640 ;
    END
  END wdata[70]
  PIN wdata[71]
    DIRECTION INPUT ;
    USE SIGNAL ;
    ANTENNAGATEAREA 0.159000 ;
    PORT
      LAYER met3 ;
        RECT 0.000 108.840 4.000 109.440 ;
    END
  END wdata[71]
  PIN wdata[7]
    DIRECTION INPUT ;
    USE SIGNAL ;
    ANTENNAGATEAREA 0.213000 ;
    PORT
      LAYER met2 ;
        RECT 135.330 0.000 135.610 4.000 ;
    END
  END wdata[7]
  PIN wdata[8]
    DIRECTION INPUT ;
    USE SIGNAL ;
    ANTENNAGATEAREA 0.159000 ;
    PORT
      LAYER met2 ;
        RECT 138.550 0.000 138.830 4.000 ;
    END
  END wdata[8]
  PIN wdata[9]
    DIRECTION INPUT ;
    USE SIGNAL ;
    ANTENNAGATEAREA 0.159000 ;
    PORT
      LAYER met2 ;
        RECT 141.770 0.000 142.050 4.000 ;
    END
  END wdata[9]
  PIN wr_n
    DIRECTION INPUT ;
    USE SIGNAL ;
    ANTENNAGATEAREA 0.126000 ;
    PORT
      LAYER met3 ;
        RECT 0.000 125.840 4.000 126.440 ;
    END
  END wr_n
  OBS
      LAYER li1 ;
        RECT 5.520 10.795 252.540 255.765 ;
      LAYER met1 ;
        RECT 4.670 10.640 253.390 255.920 ;
      LAYER met2 ;
        RECT 4.690 264.870 60.990 265.610 ;
        RECT 61.830 264.870 64.210 265.610 ;
        RECT 65.050 264.870 73.870 265.610 ;
        RECT 74.710 264.870 80.310 265.610 ;
        RECT 81.150 264.870 83.530 265.610 ;
        RECT 84.370 264.870 89.970 265.610 ;
        RECT 90.810 264.870 93.190 265.610 ;
        RECT 94.030 264.870 96.410 265.610 ;
        RECT 97.250 264.870 99.630 265.610 ;
        RECT 100.470 264.870 102.850 265.610 ;
        RECT 103.690 264.870 106.070 265.610 ;
        RECT 106.910 264.870 109.290 265.610 ;
        RECT 110.130 264.870 112.510 265.610 ;
        RECT 113.350 264.870 115.730 265.610 ;
        RECT 116.570 264.870 118.950 265.610 ;
        RECT 119.790 264.870 122.170 265.610 ;
        RECT 123.010 264.870 125.390 265.610 ;
        RECT 126.230 264.870 128.610 265.610 ;
        RECT 129.450 264.870 131.830 265.610 ;
        RECT 132.670 264.870 135.050 265.610 ;
        RECT 135.890 264.870 138.270 265.610 ;
        RECT 139.110 264.870 141.490 265.610 ;
        RECT 142.330 264.870 151.150 265.610 ;
        RECT 151.990 264.870 154.370 265.610 ;
        RECT 155.210 264.870 157.590 265.610 ;
        RECT 158.430 264.870 160.810 265.610 ;
        RECT 161.650 264.870 164.030 265.610 ;
        RECT 164.870 264.870 167.250 265.610 ;
        RECT 168.090 264.870 173.690 265.610 ;
        RECT 174.530 264.870 183.350 265.610 ;
        RECT 184.190 264.870 186.570 265.610 ;
        RECT 187.410 264.870 189.790 265.610 ;
        RECT 190.630 264.870 202.670 265.610 ;
        RECT 203.510 264.870 209.110 265.610 ;
        RECT 209.950 264.870 215.550 265.610 ;
        RECT 216.390 264.870 221.990 265.610 ;
        RECT 222.830 264.870 253.370 265.610 ;
        RECT 4.690 4.280 253.370 264.870 ;
        RECT 4.690 3.670 60.990 4.280 ;
        RECT 61.830 3.670 70.650 4.280 ;
        RECT 71.490 3.670 73.870 4.280 ;
        RECT 74.710 3.670 80.310 4.280 ;
        RECT 81.150 3.670 89.970 4.280 ;
        RECT 90.810 3.670 93.190 4.280 ;
        RECT 94.030 3.670 96.410 4.280 ;
        RECT 97.250 3.670 99.630 4.280 ;
        RECT 100.470 3.670 102.850 4.280 ;
        RECT 103.690 3.670 106.070 4.280 ;
        RECT 106.910 3.670 109.290 4.280 ;
        RECT 110.130 3.670 112.510 4.280 ;
        RECT 113.350 3.670 115.730 4.280 ;
        RECT 116.570 3.670 118.950 4.280 ;
        RECT 119.790 3.670 122.170 4.280 ;
        RECT 123.010 3.670 125.390 4.280 ;
        RECT 126.230 3.670 131.830 4.280 ;
        RECT 132.670 3.670 135.050 4.280 ;
        RECT 135.890 3.670 138.270 4.280 ;
        RECT 139.110 3.670 141.490 4.280 ;
        RECT 142.330 3.670 144.710 4.280 ;
        RECT 145.550 3.670 147.930 4.280 ;
        RECT 148.770 3.670 151.150 4.280 ;
        RECT 151.990 3.670 154.370 4.280 ;
        RECT 155.210 3.670 160.810 4.280 ;
        RECT 161.650 3.670 164.030 4.280 ;
        RECT 164.870 3.670 167.250 4.280 ;
        RECT 168.090 3.670 170.470 4.280 ;
        RECT 171.310 3.670 173.690 4.280 ;
        RECT 174.530 3.670 176.910 4.280 ;
        RECT 177.750 3.670 180.130 4.280 ;
        RECT 180.970 3.670 193.010 4.280 ;
        RECT 193.850 3.670 196.230 4.280 ;
        RECT 197.070 3.670 205.890 4.280 ;
        RECT 206.730 3.670 221.990 4.280 ;
        RECT 222.830 3.670 253.370 4.280 ;
      LAYER met3 ;
        RECT 3.990 249.240 254.430 255.845 ;
        RECT 4.400 247.840 254.430 249.240 ;
        RECT 3.990 222.040 254.430 247.840 ;
        RECT 4.400 220.640 254.430 222.040 ;
        RECT 3.990 215.240 254.430 220.640 ;
        RECT 4.400 213.840 254.430 215.240 ;
        RECT 3.990 205.040 254.430 213.840 ;
        RECT 3.990 203.640 254.030 205.040 ;
        RECT 3.990 201.640 254.430 203.640 ;
        RECT 4.400 200.240 254.030 201.640 ;
        RECT 3.990 198.240 254.430 200.240 ;
        RECT 4.400 196.840 254.430 198.240 ;
        RECT 3.990 194.840 254.430 196.840 ;
        RECT 4.400 193.440 254.430 194.840 ;
        RECT 3.990 188.040 254.430 193.440 ;
        RECT 3.990 186.640 254.030 188.040 ;
        RECT 3.990 184.640 254.430 186.640 ;
        RECT 4.400 183.240 254.030 184.640 ;
        RECT 3.990 181.240 254.430 183.240 ;
        RECT 4.400 179.840 254.030 181.240 ;
        RECT 3.990 177.840 254.430 179.840 ;
        RECT 4.400 176.440 254.430 177.840 ;
        RECT 3.990 174.440 254.430 176.440 ;
        RECT 4.400 173.040 254.030 174.440 ;
        RECT 3.990 171.040 254.430 173.040 ;
        RECT 4.400 169.640 254.030 171.040 ;
        RECT 3.990 167.640 254.430 169.640 ;
        RECT 4.400 166.240 254.030 167.640 ;
        RECT 3.990 164.240 254.430 166.240 ;
        RECT 4.400 162.840 254.030 164.240 ;
        RECT 3.990 160.840 254.430 162.840 ;
        RECT 4.400 159.440 254.030 160.840 ;
        RECT 3.990 157.440 254.430 159.440 ;
        RECT 4.400 156.040 254.030 157.440 ;
        RECT 3.990 154.040 254.430 156.040 ;
        RECT 4.400 152.640 254.030 154.040 ;
        RECT 3.990 150.640 254.430 152.640 ;
        RECT 4.400 149.240 254.030 150.640 ;
        RECT 3.990 147.240 254.430 149.240 ;
        RECT 4.400 145.840 254.030 147.240 ;
        RECT 3.990 143.840 254.430 145.840 ;
        RECT 4.400 142.440 254.030 143.840 ;
        RECT 3.990 140.440 254.430 142.440 ;
        RECT 4.400 139.040 254.030 140.440 ;
        RECT 3.990 137.040 254.430 139.040 ;
        RECT 4.400 135.640 254.030 137.040 ;
        RECT 3.990 133.640 254.430 135.640 ;
        RECT 4.400 132.240 254.030 133.640 ;
        RECT 3.990 130.240 254.430 132.240 ;
        RECT 4.400 128.840 254.030 130.240 ;
        RECT 3.990 126.840 254.430 128.840 ;
        RECT 4.400 125.440 254.030 126.840 ;
        RECT 3.990 123.440 254.430 125.440 ;
        RECT 4.400 122.040 254.030 123.440 ;
        RECT 3.990 120.040 254.430 122.040 ;
        RECT 4.400 118.640 254.030 120.040 ;
        RECT 3.990 116.640 254.430 118.640 ;
        RECT 4.400 115.240 254.030 116.640 ;
        RECT 3.990 113.240 254.430 115.240 ;
        RECT 4.400 111.840 254.030 113.240 ;
        RECT 3.990 109.840 254.430 111.840 ;
        RECT 4.400 108.440 254.030 109.840 ;
        RECT 3.990 106.440 254.430 108.440 ;
        RECT 4.400 105.040 254.030 106.440 ;
        RECT 3.990 103.040 254.430 105.040 ;
        RECT 4.400 101.640 254.430 103.040 ;
        RECT 3.990 99.640 254.430 101.640 ;
        RECT 4.400 98.240 254.030 99.640 ;
        RECT 3.990 96.240 254.430 98.240 ;
        RECT 4.400 94.840 254.030 96.240 ;
        RECT 3.990 92.840 254.430 94.840 ;
        RECT 4.400 91.440 254.030 92.840 ;
        RECT 3.990 89.440 254.430 91.440 ;
        RECT 4.400 88.040 254.030 89.440 ;
        RECT 3.990 86.040 254.430 88.040 ;
        RECT 4.400 84.640 254.430 86.040 ;
        RECT 3.990 82.640 254.430 84.640 ;
        RECT 4.400 81.240 254.430 82.640 ;
        RECT 3.990 79.240 254.430 81.240 ;
        RECT 4.400 77.840 254.030 79.240 ;
        RECT 3.990 75.840 254.430 77.840 ;
        RECT 4.400 74.440 254.030 75.840 ;
        RECT 3.990 72.440 254.430 74.440 ;
        RECT 4.400 71.040 254.430 72.440 ;
        RECT 3.990 69.040 254.430 71.040 ;
        RECT 3.990 67.640 254.030 69.040 ;
        RECT 3.990 65.640 254.430 67.640 ;
        RECT 4.400 64.240 254.430 65.640 ;
        RECT 3.990 62.240 254.430 64.240 ;
        RECT 4.400 60.840 254.430 62.240 ;
        RECT 3.990 58.840 254.430 60.840 ;
        RECT 4.400 57.440 254.030 58.840 ;
        RECT 3.990 55.440 254.430 57.440 ;
        RECT 3.990 54.040 254.030 55.440 ;
        RECT 3.990 10.715 254.430 54.040 ;
      LAYER met4 ;
        RECT 23.295 40.975 23.940 248.705 ;
        RECT 26.340 40.975 174.240 248.705 ;
        RECT 176.640 40.975 177.540 248.705 ;
        RECT 179.940 40.975 240.745 248.705 ;
  END
END dff_ram_8x72
END LIBRARY

